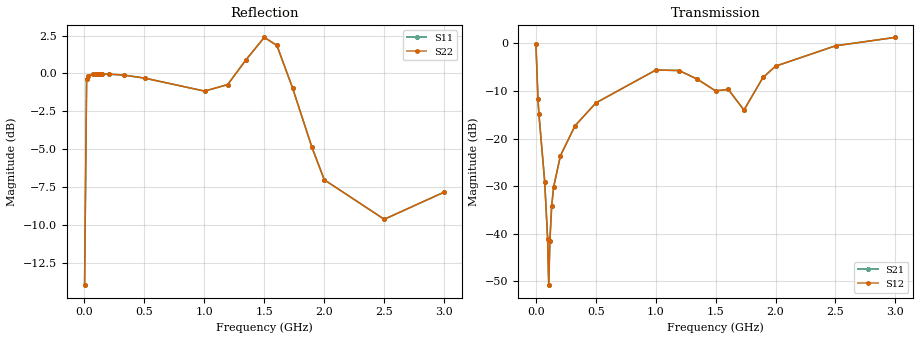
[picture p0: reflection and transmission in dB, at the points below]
!s-Parameter Generated by FASTRON Sdn. Bhd.
!FASTRON P/N : MICC-3R9X
!Keysight Technologies,E4991B,MY54100416,A.01.15
!Date: Fri Aug 28 10:00:29 2026
!Version  : Rev00 Fri Aug 28 10:00:29 2026
!Data & Calibration Information:
!PortZ  Port1:50+j0  Port2:50+j0
!When reading, reference impedance value at option line is always used.
! Remarks : This data is being provided solely for informational purposes.
!Freq	S11	S21	S12	S22
# Hz S dB R 50
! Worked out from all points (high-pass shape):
!   1601 points, 1 MHz to 3 GHz, reference 50 ohm
!   highest |S21| = 1.23 dB at 3 GHz (marker M1); lowest = -50.8 dB at 107.8 MHz (marker M2)
!   |S21| within 3 dB of the highest: start of sweep to 3.365 MHz; 2.31 GHz to end of sweep
!   lowest |S11| = -14.0 dB at 1 MHz (marker M3), VSWR 1.50, Z = 50.6 + j20.5 ohm
!   |S11| at or under -10 dB: start of sweep to 1.934 MHz
!   |S22| runs from -14.0 to 2.4 dB; largest |S21 - S12| = 0
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1000000  -13.99 76.9  -0.22 -11.5  -0.22 -11.5  -13.99 76.9
1.786938e7  -0.35 15.2  -11.65 -73.9  -11.65 -73.9  -0.35 15.2
2.536688e7  -0.17 10.5  -14.76 -78.6  -14.76 -78.6  -0.17 10.5
7.410062e7  -0.03 2.0  -29.04 -83.2  -29.04 -83.2  -0.03 2.0
9.84675e7  -0.03 0.5  -41.09 -70.4  -41.09 -70.4  -0.03 0.5
1.078394e8  -0.03 -0.0  -50.78 1.9  -50.78 1.9  -0.03 -0.0
1.172112e8  -0.02 -0.5  -41.51 69.9  -41.51 69.9  -0.02 -0.5
1.322062e8  -0.03 -1.1  -34.17 80.4  -34.17 80.4  -0.03 -1.1
1.490756e8  -0.03 -1.8  -30.13 82.9  -30.13 82.9  -0.03 -1.8
2.053069e8  -0.05 -3.8  -23.61 83.6  -23.61 83.6  -0.05 -3.8
3.271412e8  -0.11 -7.8  -17.33 80.8  -17.33 80.8  -0.11 -7.8
5.014581e8  -0.31 -13.7  -12.52 74.8  -12.52 74.8  -0.31 -13.7
1.001916e9  -1.17 -31.6  -5.62 60.8  -5.62 60.8  -1.17 -31.6
1.194977e9  -0.74 -30.9  -5.73 65.7  -5.73 65.7  -0.74 -30.9
1.346801e9  0.89 -22.2  -7.53 93.5  -7.53 93.5  0.89 -22.2
1.5005e9  2.38 -0.9  -10.01 176.1  -10.01 176.1  2.38 -0.9
1.605465e9  1.85 11.7  -9.68 -130.2  -9.68 -130.2  1.85 11.7
1.736671e9  -0.97 10.2  -14.02 -52.9  -14.02 -52.9  -0.97 10.2
1.895993e9  -4.84 -7.3  -7.17 9.6  -7.17 9.6  -4.84 -7.3
2.000958e9  -7.03 -12.8  -4.81 9.9  -4.81 9.9  -7.03 -12.8
2.501416e9  -9.64 -70.2  -0.53 19.2  -0.53 19.2  -9.64 -70.2
3e9  -7.85 -101.6  1.23 20.2  1.23 20.2  -7.85 -101.6
